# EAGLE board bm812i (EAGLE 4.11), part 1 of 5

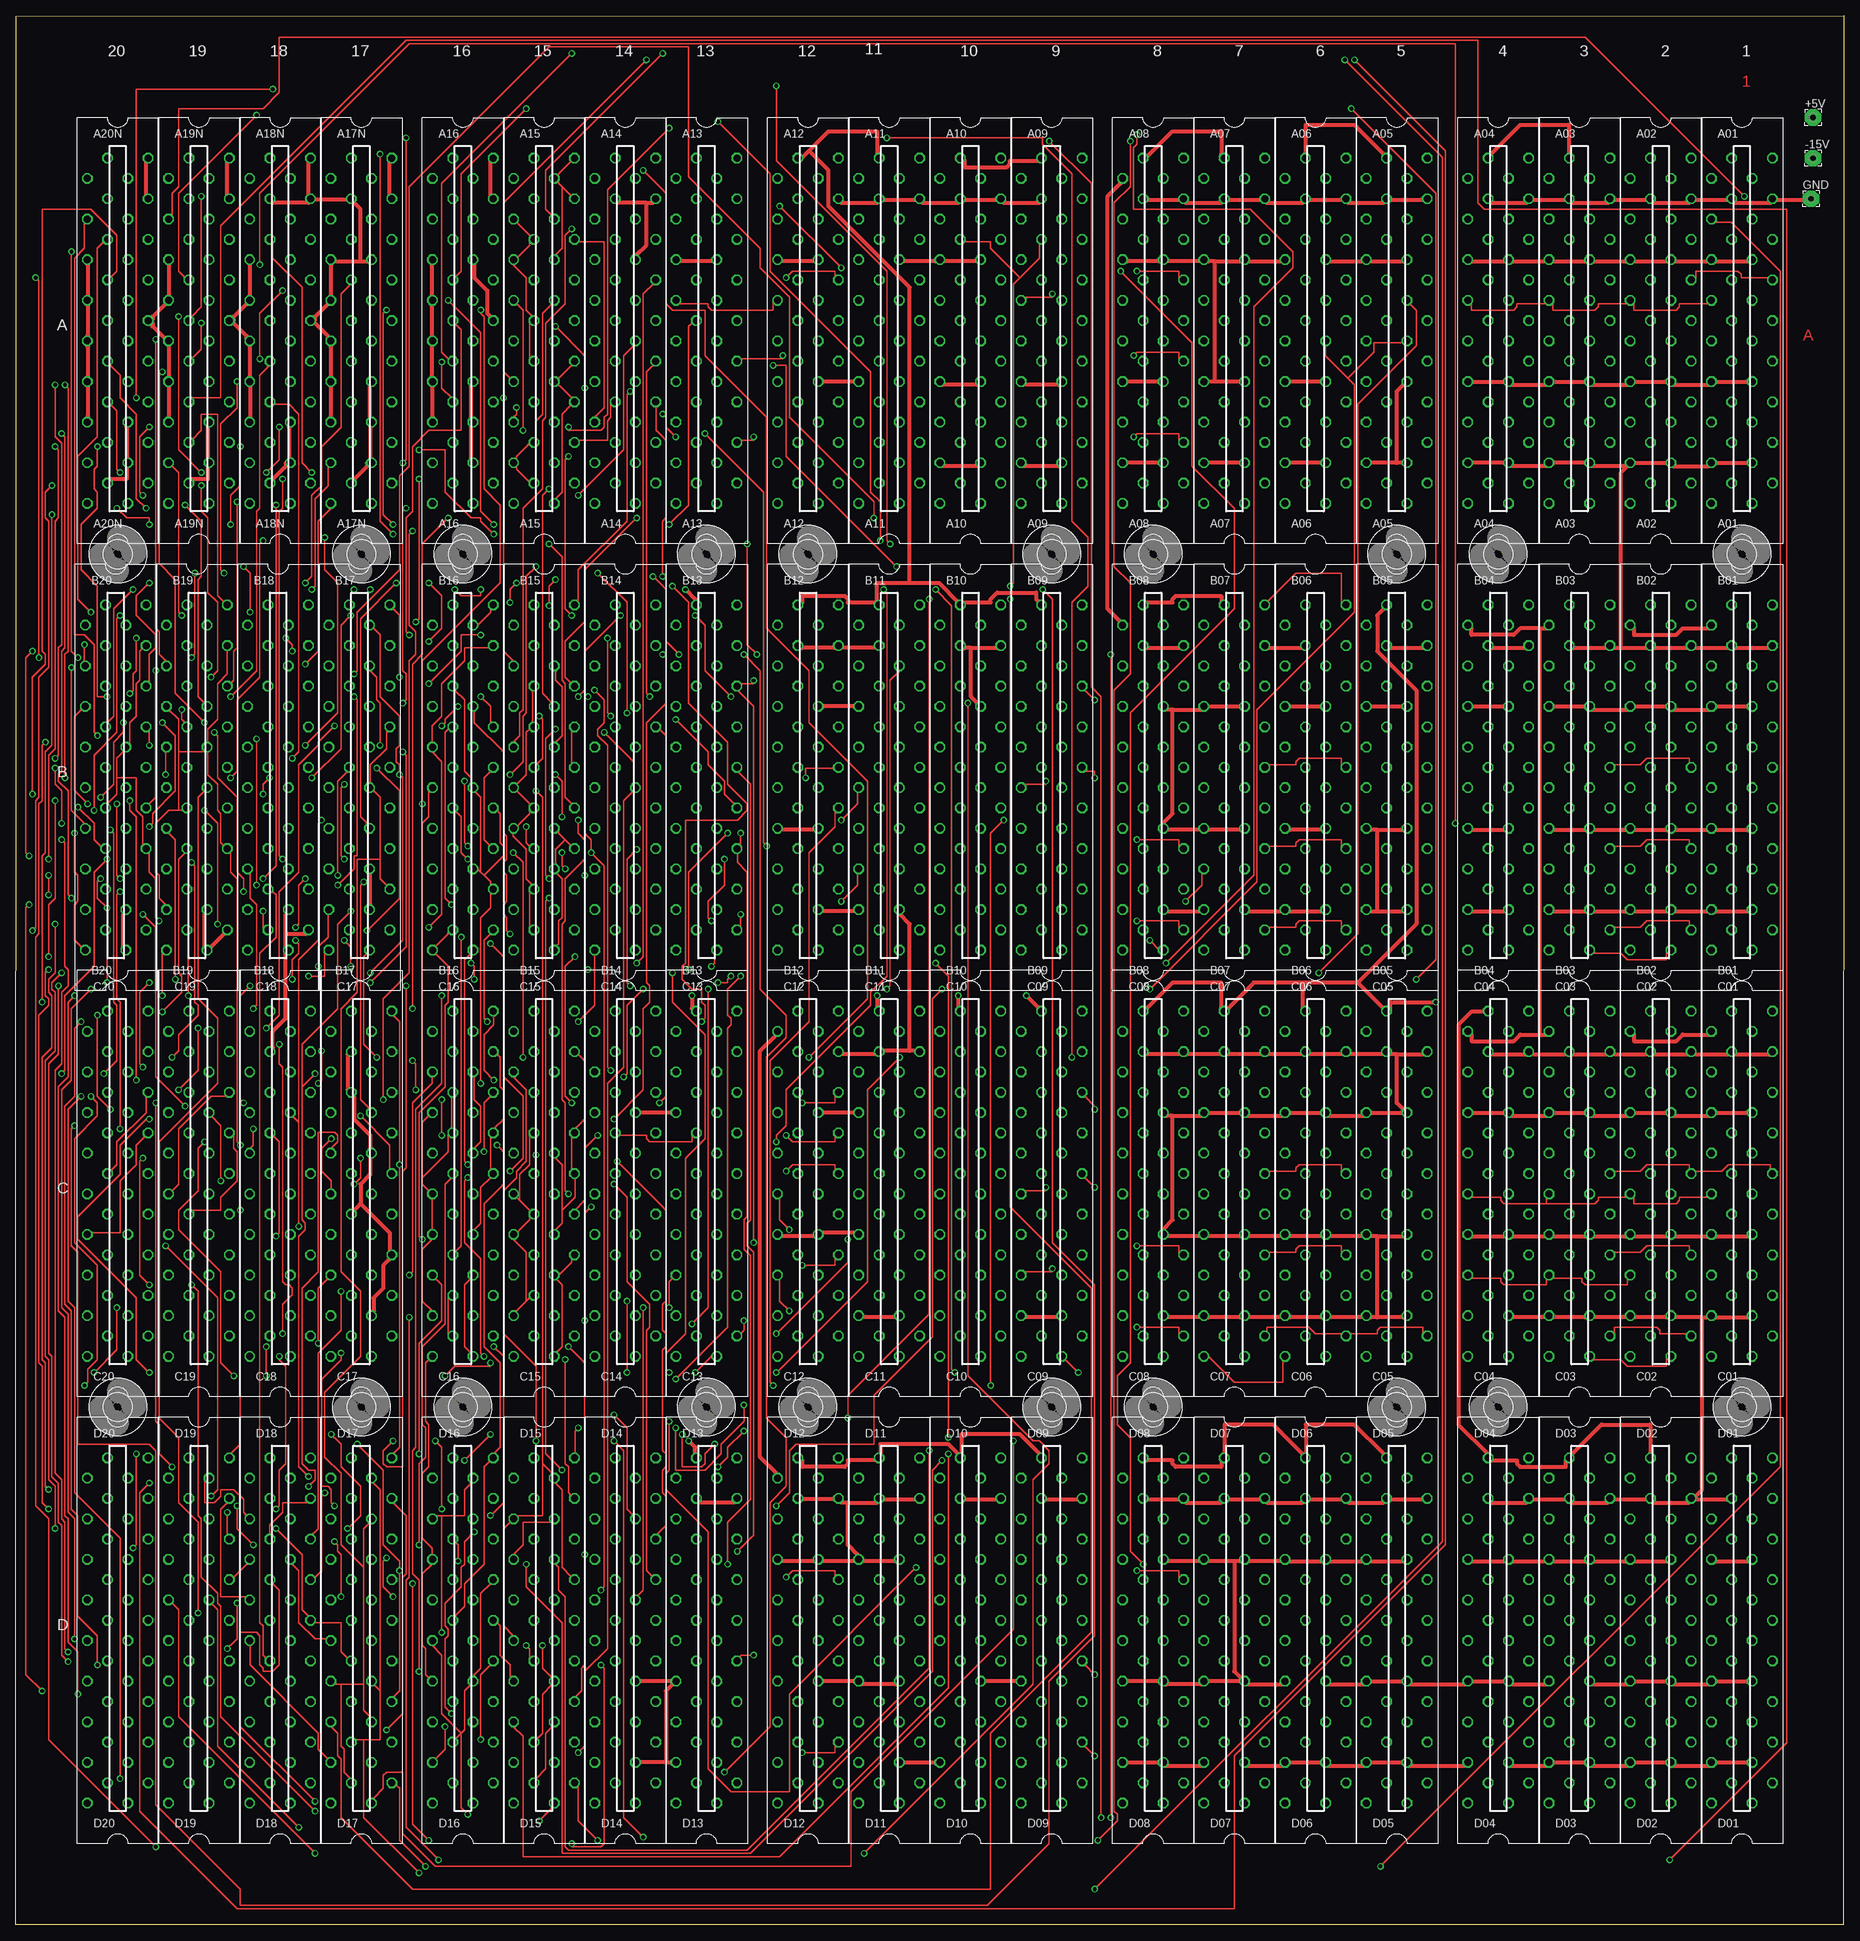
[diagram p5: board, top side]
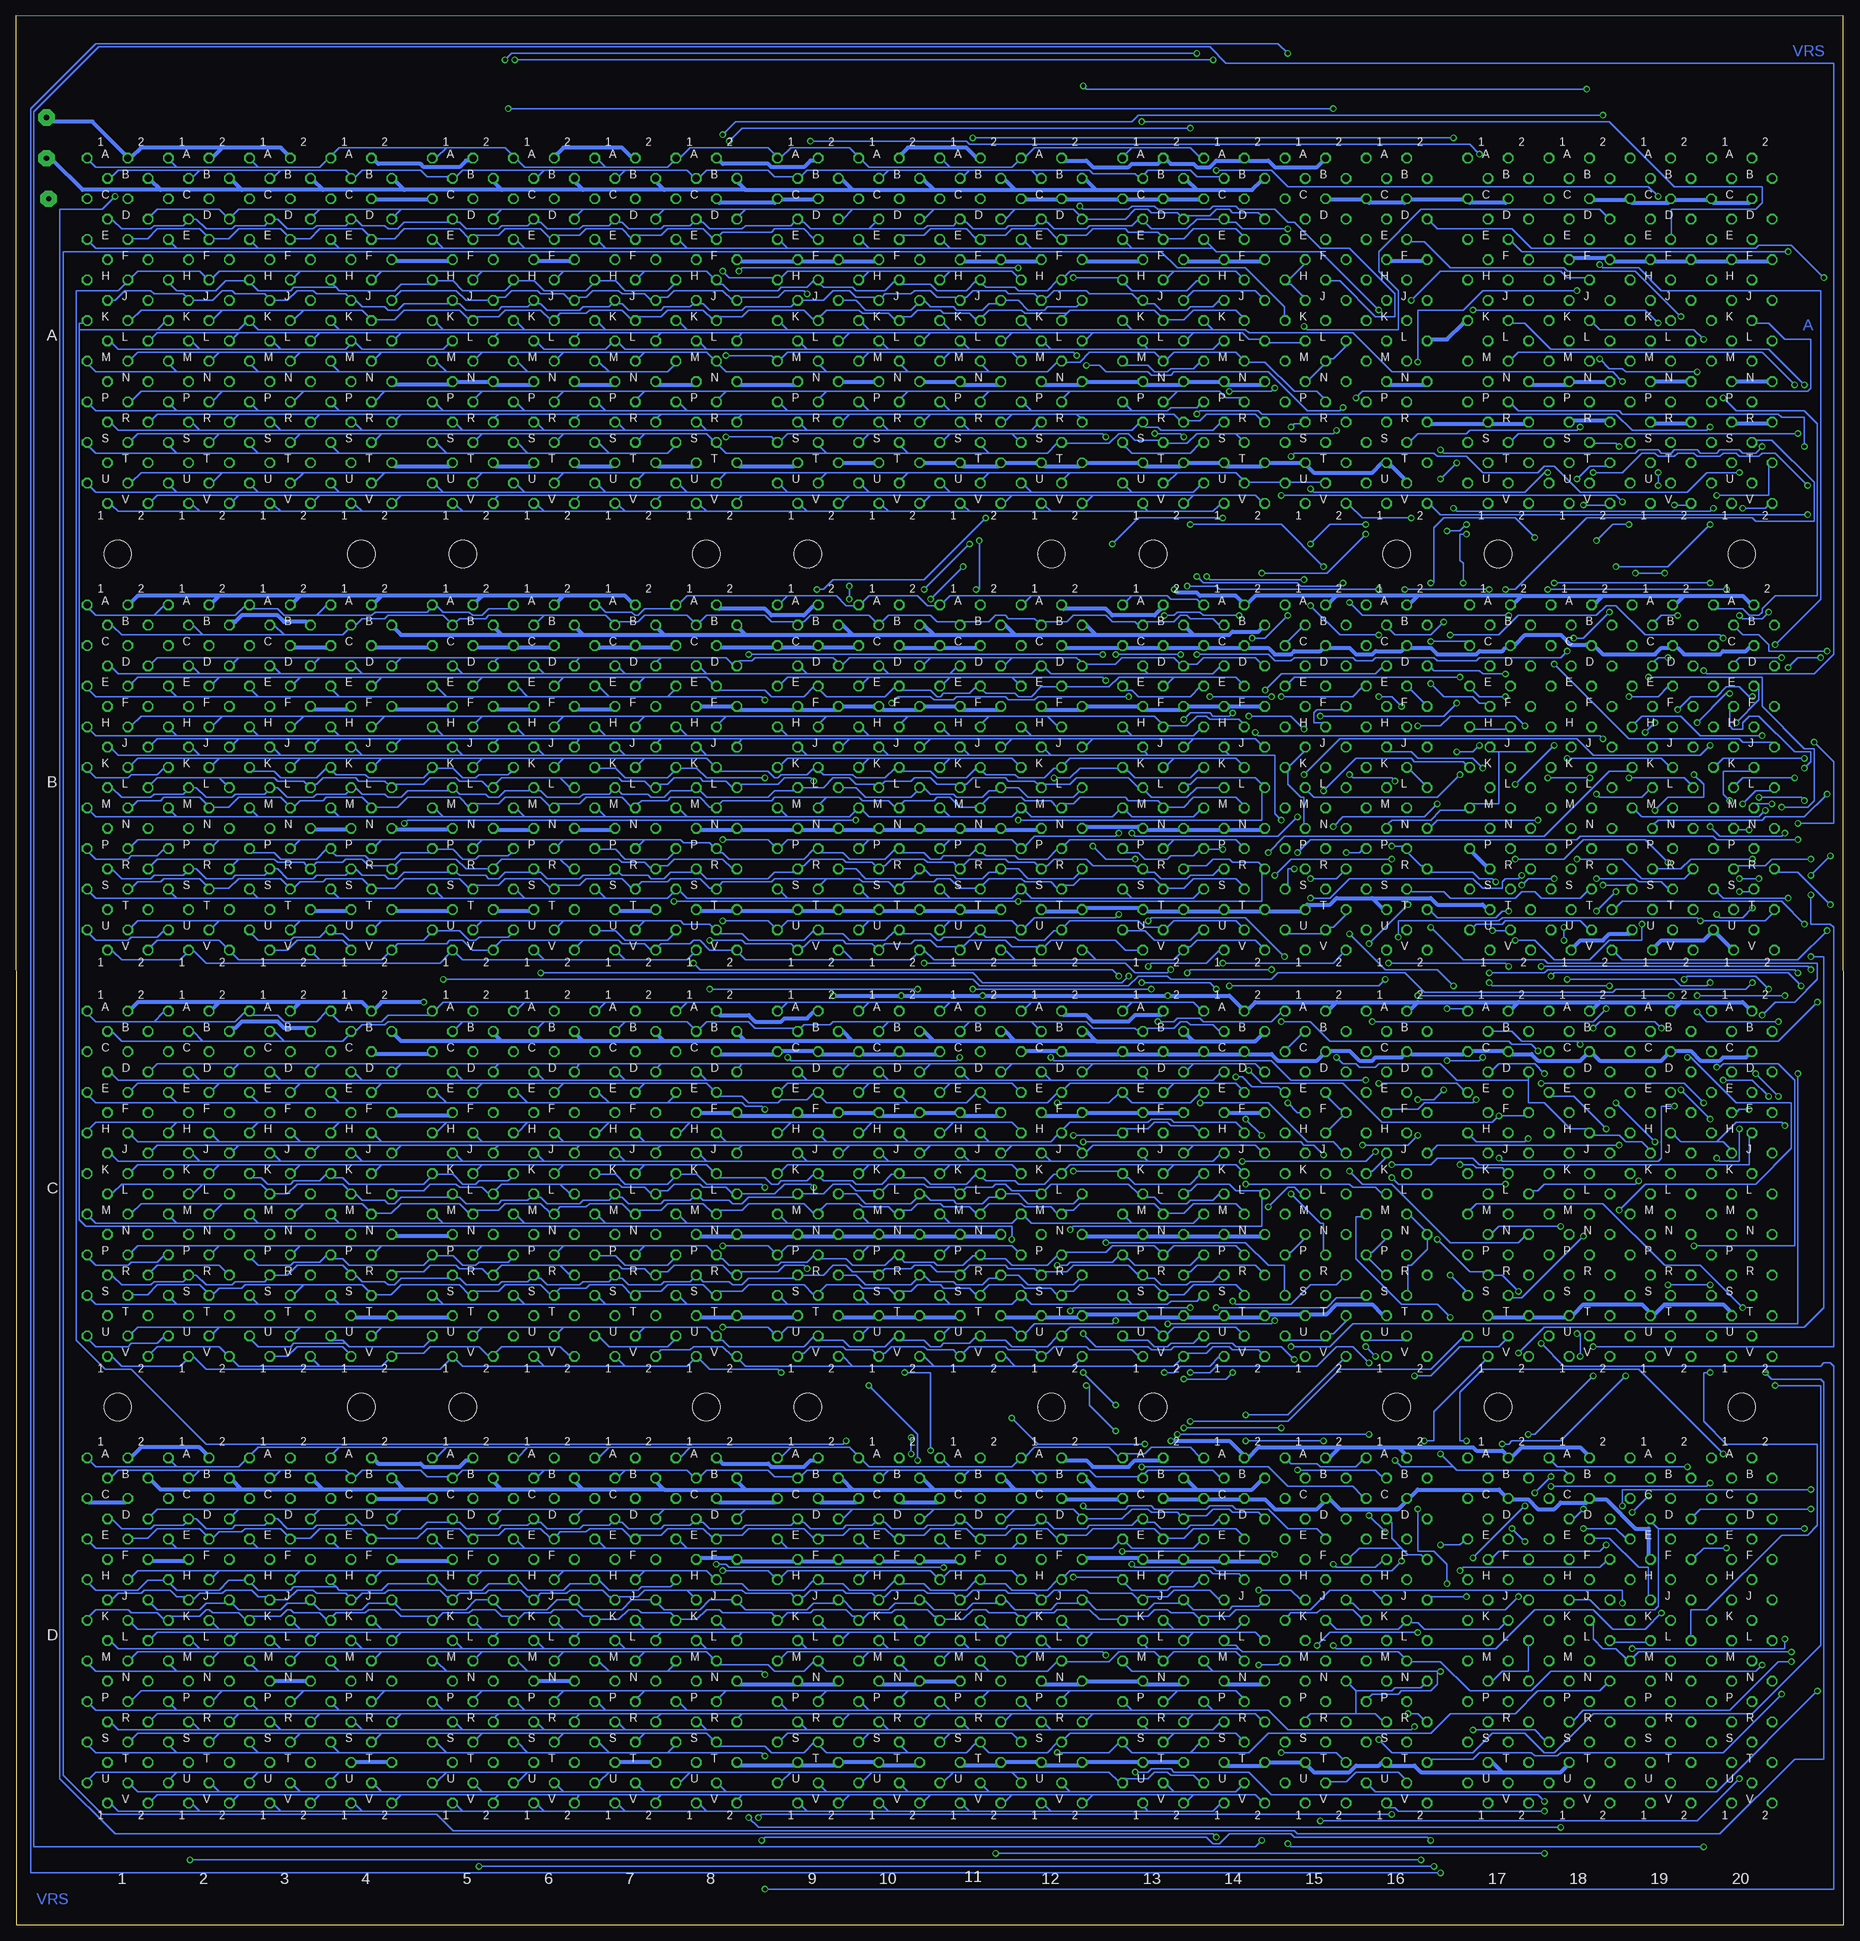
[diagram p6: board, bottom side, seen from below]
Size 285.81 x 298.44 mm. Coordinates in mm from the lower left corner, seen from the top.
Outline: 285.78,0 0,0 0.03,298.42 285.81,298.44 285.78,0
Copper layers (1*2*15*16): Top 0.035mm / dielectric 1.5mm / Route2 0.035mm / dielectric 0.15mm / Route15 0.035mm / dielectric 0.2mm / Bottom 0.035mm
Design rules "10mils": minimum track width 10mil, minimum drill 24mil, track to track 5mil, track to pad 10mil, pad to pad 10mil, via to via 5mil, smd to smd 10mil, copper to edge 40mil, drill to drill 10mil, minimum pad ring 10mil, minimum via ring 8mil, stop-mask expansion 0mil, vias tented up to drill 0mil, thermal gap 10mil
Net classes: 1 Power: width 0.635 mm

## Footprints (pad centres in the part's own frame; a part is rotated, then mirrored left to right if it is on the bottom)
2,54/0,8 = drill 0.813 pad 2.54 octagon: 1 0,0
H807 = drill 1.092 octagon: A1 4.763,28.575; A2 -1.587,28.575; B1 1.587,25.4; B2 -4.763,25.4; C1 4.763,22.225; C2 -1.587,22.225; D1 1.587,19.05; D2 -4.763,19.05; E1 4.763,15.875; E2 -1.587,15.875; F1 1.587,12.7; F2 -4.763,12.7; H1 4.763,9.525; H2 -1.587,9.525; J1 1.587,6.35; J2 -4.763,6.35; K1 4.763,3.175; K2 -1.587,3.175; L1 1.587,0; L2 -4.763,0; M1 4.763,-3.175; M2 -1.587,-3.175; N1 1.587,-6.35; N2 -4.763,-6.35; P1 4.763,-9.525; P2 -1.587,-9.525; R1 1.587,-12.7; R2 -4.763,-12.7; S1 4.763,-15.875; S2 -1.587,-15.875; T1 1.587,-19.05; T2 -4.763,-19.05; U1 4.763,-22.225; U2 -1.587,-22.225; V1 1.587,-25.4; V2 -4.763,-25.4
4,3 = hole 4.3: 0,0

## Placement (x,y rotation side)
+5V  [2,54/0,8]  281.02,282.56 0 top
-15V  [2,54/0,8]  281.02,276.21 0 top
A01  [H807]  269.91,247.64 0 top
A02  [H807]  257.21,247.64 0 top
A03  [H807]  244.51,247.64 0 top
A04  [H807]  231.81,247.64 0 top
A05  [H807]  215.94,247.64 0 top
A06  [H807]  203.24,247.64 0 top
A07  [H807]  190.54,247.64 0 top
A08  [H807]  177.84,247.64 0 top
A09  [H807]  161.96,247.64 0 top
A10  [H807]  149.26,247.64 0 top
A11  [H807]  136.56,247.64 0 top
A12  [H807]  123.86,247.64 0 top
A13  [H807]  107.99,247.64 0 top
A14  [H807]  95.29,247.64 0 top
A15  [H807]  82.59,247.64 0 top
A16  M903  [H807]  69.89,247.64 0 top
A17N  M903  [H807]  54.01,247.64 0 top
A18N  M903  [H807]  41.31,247.64 0 top
A19N  M903  [H807]  28.61,247.64 0 top
A20N  M903  [H807]  15.91,247.64 0 top
B01  [H807]  269.91,177.79 0 top
B02  [H807]  257.21,177.79 0 top
B03  [H807]  244.51,177.79 0 top
B04  [H807]  231.81,177.79 0 top
B05  [H807]  215.94,177.79 0 top
B06  [H807]  203.24,177.79 0 top
B07  [H807]  190.54,177.79 0 top
B08  [H807]  177.84,177.79 0 top
B09  [H807]  161.96,177.79 0 top
B10  [H807]  149.26,177.79 0 top
B11  [H807]  136.56,177.79 0 top
B12  [H807]  123.86,177.79 0 top
B13  [H807]  107.99,177.79 0 top
B14  [H807]  95.29,177.79 0 top
B15  [H807]  82.59,177.79 0 top
B16  [H807]  69.89,177.79 0 top
B17  [H807]  53.69,177.79 0 top
B18  [H807]  40.99,177.79 0 top
B19  [H807]  28.29,177.79 0 top
B20  [H807]  15.59,177.79 0 top
C01  [H807]  269.91,114.29 0 top
C02  [H807]  257.21,114.29 0 top
C03  [H807]  244.51,114.29 0 top
C04  [H807]  231.81,114.29 0 top
C05  [H807]  215.94,114.29 0 top
C06  [H807]  203.24,114.29 0 top
C07  [H807]  190.54,114.29 0 top
C08  [H807]  177.84,114.29 0 top
C09  [H807]  161.96,114.29 0 top
C10  [H807]  149.26,114.29 0 top
C11  [H807]  136.56,114.29 0 top
C12  [H807]  123.86,114.29 0 top
C13  [H807]  107.99,114.29 0 top
C14  [H807]  95.29,114.29 0 top
C15  [H807]  82.59,114.29 0 top
C16  [H807]  69.89,114.29 0 top
C17  M206X  [H807]  54.01,114.29 0 top
C18  M310  [H807]  41.31,114.29 0 top
C19  M310  [H807]  28.61,114.29 0 top
C20  M310  [H807]  15.91,114.29 0 top
D01  [H807]  269.91,44.44 0 top
D02  [H807]  257.21,44.44 0 top
D03  [H807]  244.51,44.44 0 top
D04  [H807]  231.81,44.44 0 top
D05  [H807]  215.94,44.44 0 top
D06  [H807]  203.24,44.44 0 top
D07  [H807]  190.54,44.44 0 top
D08  [H807]  177.84,44.44 0 top
D09  [H807]  161.96,44.44 0 top
D10  [H807]  149.26,44.44 0 top
D11  [H807]  136.56,44.44 0 top
D12  [H807]  123.86,44.44 0 top
D13  [H807]  107.99,44.44 0 top
D14  [H807]  95.29,44.44 0 top
D15  M206X  [H807]  82.59,44.44 0 top
D16  M206X  [H807]  69.89,44.44 0 top
D17  M206X  [H807]  54.01,44.44 0 top
D18  [H807]  41.31,44.44 0 top
D19  M921  [H807]  28.61,44.44 0 top
D20  H807  [H807]  15.91,44.44 0 top
GND  [2,54/0,8]  280.71,269.86 0 top
U$20  [4,3]  15.91,214.3 0 top
U$66  [4,3]  54.01,214.3 0 top
U$67  [4,3]  69.89,214.3 0 top
U$68  [4,3]  107.99,214.3 0 top
U$69  [4,3]  123.86,214.3 0 top
U$70  [4,3]  161.96,214.3 0 top
U$71  [4,3]  177.84,214.3 0 top
U$72  [4,3]  215.94,214.3 0 top
U$73  [4,3]  231.81,214.3 0 top
U$74  [4,3]  269.91,214.3 0 top
U$75  [4,3]  269.91,80.95 0 top
U$76  [4,3]  231.81,80.95 0 top
U$77  [4,3]  215.94,80.95 0 top
U$78  [4,3]  177.84,80.95 0 top
U$79  [4,3]  161.96,80.95 0 top
U$80  [4,3]  123.86,80.95 0 top
U$81  [4,3]  107.99,80.95 0 top
U$82  [4,3]  69.89,80.95 0 top
U$83  [4,3]  54.01,80.95 0 top
U$86  [4,3]  15.91,80.95 0 top

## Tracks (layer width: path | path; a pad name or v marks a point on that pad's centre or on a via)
-15V
  Top 0.635: B01.B2 264.7,202.68 260.64,202.68 259.62,201.66 253.02,201.66 253.02,202.68 B02.B2 | 238.29,202.68 235.24,202.68 234.22,201.66 227.62,201.66 227.62,202.68 B04.B2 | 238.29,202.68 239.3,202.68 B03.B2 | C01.B2 264.7,139.18 260.64,139.18 259.62,138.16 253.02,138.16 253.02,139.18 C02.B2 | 238.29,139.18 235.24,139.18 234.22,138.16 227.62,138.16 227.62,139.18 C04.B2 | 238.29,139.18 239.3,139.18 C03.B2 | D12.B2 118.91,70.6 116.37,73.14 116.37,136.64 118.91,139.18 C12.B2 | 238.29,139.18 238.29,202.68 | A08.B2 172.76,272.28 170.72,270.24 170.72,205.73 172.76,203.7 B08.B2
  Bottom 0.635: 101.13,271.26 92.49,271.26 90.97,272.78 A14.B2 | 101.13,271.26 102.65,272.78 A13.B2 | 116.88,271.26 118.4,272.78 A12.B2 | 116.88,271.26 101.13,271.26 | 129.58,271.26 131.1,272.78 A11.B2 | 129.58,271.26 116.88,271.26 | 142.28,271.26 143.8,272.78 A10.B2 | 142.28,271.26 129.58,271.26 | 154.98,271.26 156.5,272.78 A09.B2 | 154.98,271.26 142.28,271.26 | 171.74,271.26 172.76,272.28 A08.B2 | 171.74,271.26 154.98,271.26 | 184.44,271.26 185.46,272.28 A07.B2 | 171.74,271.26 184.44,271.26 | 197.14,271.26 198.16,272.28 A06.B2 | 184.44,271.26 197.14,271.26 | 209.84,271.26 210.86,272.28 A05.B2 | 197.14,271.26 209.84,271.26 | 225.08,271.26 226.6,272.78 A04.B2 | 209.84,271.26 225.08,271.26 | 237.78,271.26 239.3,272.78 A03.B2 | 225.08,271.26 237.78,271.26 | 250.48,271.26 252,272.78 A02.B2 | 237.78,271.26 250.48,271.26 | 263.18,271.26 264.7,272.78 A01.B2 | 250.48,271.26 263.18,271.26 | 263.18,271.26 275.37,271.26 279.94,275.83 -15V.1 | B03.B2 240.32,203.7 243.88,203.7 244.89,204.71 250.48,204.71 251.5,203.7 252,203.7 B02.B2 | 101.64,201.66 96.05,201.66 95.54,202.17 91.48,202.17 90.97,202.68 B14.B2 | 101.64,201.66 102.65,202.68 B13.B2 | 116.88,201.66 118.4,203.19 B12.B2 | 116.88,201.66 101.64,201.66 | 129.58,201.66 131.1,203.19 B11.B2 | 129.58,201.66 116.88,201.66 | 142.28,201.66 143.8,203.19 B10.B2 | 142.28,201.66 129.58,201.66 | 154.98,201.66 156.5,203.19 B09.B2 | 154.98,201.66 142.28,201.66 | 171.74,201.66 172.76,202.68 B08.B2 | 171.74,201.66 154.98,201.66 | 184.44,201.66 185.46,202.68 B07.B2 | 184.44,201.66 171.74,201.66 | 197.14,201.66 198.16,202.68 B06.B2 | 197.14,201.66 184.44,201.66 | 209.84,201.66 210.86,202.68 B05.B2
  Bottom 0.635: 209.84,201.66 197.14,201.66 | 209.84,201.66 225.59,201.66 226.6,202.68 B04.B2 | 101.13,68.06 92.49,68.06 90.97,69.58 D14.B2 | 101.13,68.06 102.65,69.58 D13.B2 | 116.88,68.06 118.4,69.58 D12.B2 | 116.88,68.06 101.13,68.06 | 129.58,68.06 131.1,69.58 D11.B2 | 129.58,68.06 116.88,68.06 | 142.28,68.06 143.8,69.58 D10.B2 | 142.28,68.06 129.58,68.06 | 154.98,68.06 156.5,69.58 D09.B2 | 154.98,68.06 142.28,68.06 | 171.74,68.06 172.76,69.08 D08.B2 | 171.74,68.06 154.98,68.06 | 184.44,68.06 185.46,69.08 D07.B2 | 184.44,68.06 171.74,68.06 | 197.14,68.06 198.16,69.08 D06.B2 | 184.44,68.06 197.14,68.06 | 209.84,68.06 210.86,69.08 D05.B2 | 197.14,68.06 209.84,68.06 | 225.08,68.06 226.6,69.58 D04.B2 | 209.84,68.06 225.08,68.06 | 237.78,68.06 239.3,69.58 D03.B2 | 225.08,68.06 237.78,68.06 | 250.48,68.06 252,69.58 D02.B2 | 237.78,68.06 250.48,68.06 | 250.48,68.06 263.18,68.06 264.7,69.58 D01.B2 | C03.B2 240.32,140.2 243.88,140.2 244.89,141.21 250.48,141.21 251.5,140.2 252,140.2 C02.B2 | 101.64,138.16 91.98,138.16 90.97,139.18 C14.B2 | 101.64,138.16 102.65,139.18 C13.B2 | 116.88,138.16 118.4,139.69 C12.B2 | 116.88,138.16 101.64,138.16 | 129.58,138.16 131.1,139.69 C11.B2 | 116.88,138.16 129.58,138.16 | 142.28,138.16 143.8,139.69 C10.B2 | 129.58,138.16 142.28,138.16 | 154.98,138.16 156.5,139.69 C09.B2 | 142.28,138.16 154.98,138.16 | 171.74,138.16 172.76,139.18 C08.B2 | 154.98,138.16 171.74,138.16 | 184.44,138.16 185.46,139.18 C07.B2 | 171.74,138.16 184.44,138.16 | 197.14,138.16 198.16,139.18 C06.B2 | 184.44,138.16 197.14,138.16 | 209.84,138.16 210.86,139.18 C05.B2 | 197.14,138.16 209.84,138.16 | 209.84,138.16 225.59,138.16 226.6,139.18 C04.B2
A15U1
  Top 0.254: 85.38,271.77 84.87,272.28 84.87,272.78 A15.B1 84.87,273.29 84.87,273.8 86.9,275.83 A15.A1 | 85.38,271.77 86.9,270.24 A15.C1 | 85.38,271.77 85.38,262.12 84.36,261.1 A15.F1 | A15.U2 80.3,225.54 78.27,227.57 78.27,228.08 A15.T2 78.27,229.1 78.27,229.6 80.3,231.64 A15.S2 81.32,232.14 81.32,235.19 82.33,236.21 82.33,251.96 83.86,253.48 A15.J1
  Bottom 0.254: A15.J1 84.36,254.5 86.4,256.53 86.9,256.53 A15.H1 86.9,257.54 86.4,257.54 84.36,259.58 A15.F1 | 104.18,227.06 105.7,225.54 A13.U2 | 104.18,227.06 95.03,227.06 94.02,226.05 A14.U2 93,225.54 87.92,225.54 A15.U1 86.9,225.54 81.32,225.54 A15.U2 | 120.94,227.06 121.96,226.05 A12.U2 | 104.18,227.06 120.94,227.06 | 133.64,227.06 134.66,226.05 A11.U2 | 120.94,227.06 133.64,227.06 | 146.34,227.06 147.36,226.05 A10.U2 | 133.64,227.06 146.34,227.06 | 159.04,227.06 160.06,226.05 A09.U2 | 146.34,227.06 159.04,227.06 | 174.79,227.06 175.8,226.05 A08.U2 | 159.04,227.06 174.79,227.06 | 187.49,227.06 188.5,226.05 A07.U2 | 174.79,227.06 187.49,227.06 | 200.19,227.06 201.2,226.05 A06.U2 | 187.49,227.06 200.19,227.06 | 212.89,227.06 213.9,226.05 A05.U2 | 200.19,227.06 212.89,227.06 | 228.13,227.06 229.65,225.54 A04.U2 | 212.89,227.06 228.13,227.06 | 240.83,227.06 242.35,225.54 A03.U2 | 228.13,227.06 240.83,227.06 | 253.53,227.06 255.05,225.54 A02.U2 | 240.83,227.06 253.53,227.06 | 253.53,227.06 266.23,227.06 267.75,225.54 A01.U2
A15V1
  Top 0.254: A15.V1 84.36,223 85.38,224.02 85.38,236.21 86.9,237.73 A15.P1 86.9,238.75 84.87,240.78 84.87,241.29 | A15.D2 78.27,266.18 80.3,264.15 80.3,263.64 A15.E2 80.3,263.13 80.3,262.62 78.27,260.59 A15.F2 77.76,259.58 79.79,257.54 79.79,252.46 80.81,251.45 A15.K2 80.3,250.43 80.3,244.84 A15.M2 | 84.87,241.29 84.87,241.8 86.9,243.83 A15.M1 | 84.87,241.29 A15.N1
  Bottom 0.254: A15.N1 83.86,241.8 83.35,241.8 81.32,243.83 A15.M2 80.3,244.84 79.79,244.84 77.76,246.88 A15.L2
B17S1
  Top 0.254: B17.H1 57.95,186.93 57.95,183.88 55.41,181.34 55.41,178.3 B17.L1 55.92,177.28 56.93,176.26 56.93,166.61 | 56.93,166.61 56.93,163.56 57.95,162.55 B17.S1 | 50.84,37.58 54.39,37.58 | 50.84,37.58 49.82,37.58 D17.N2 | 54.39,37.58 54.39,33.52 55.41,32.5 D17.R1 | 50.84,37.58 50.84,27.93 51.34,27.42 51.34,23.86 52.36,22.85 D17.U2 | 54.39,37.58 54.39,55.87 | 54.39,55.87 54.39,61.96 55.41,62.98 D17.D1 | 56.93,166.61 53.38,166.61 53.38,145.78 50.84,143.24 50.84,102.1 53.88,99.05 53.88,88.89 48.3,83.3 48.3,73.14 50.84,70.6 50.84,59.42 54.39,55.87
  Bottom 0.254: B17.H2 52.87,186.93 57.95,186.93 B17.H1
B17V1  (via drill 0.61)
  Top 0.254: B16.B1 72.17,203.19 74.2,205.22 74.2,205.73 B16.A1 | v56.42,135.62 54.39,137.66 54.39,151.37 54.9,151.88 B17.V1 | v62.01,135.12 62.52,134.61 v62.52,130.54 | v66.58,123.43 v66.58,129.02 | v75.22,121.91 76.24,120.89 76.24,115.81 73.19,112.76 73.19,90.41 75.73,87.87 75.73,74.66 74.71,73.65 D16.A1 74.2,72.63 73.19,71.62 73.19,56.38 70.14,53.33 70.14,49.77 68.62,48.25 D16.K2 | v62.52,203.7 63.03,204.2 v63.03,226.05 | v60.49,228.59 61,229.1 v61,279.39 | v136.18,279.39 160.56,279.39 160.56,278.37 165.14,273.8 165.14,219.44 167.68,216.9 167.68,209.28 165.14,206.74 v165.14,135.62 | v138.21,135.62 133.13,130.54 133.13,100.57 v118.91,86.35 | v113.83,81.27 113.83,78.73 110.27,75.17 110.27,73.65 107.73,71.11 103.16,71.11 v103.16,77.71 | v87.92,77.71 87.41,77.2 87.41,73.65 D15.A1
  Bottom 0.254: D17.K2 52.87,47.23 53.88,46.22 65.57,46.22 66.58,47.23 67.6,47.23 D16.K2 68.62,47.23 69.63,46.22 79.28,46.22 80.3,47.23 D15.K2 | v56.42,135.62 56.93,135.12 v62.01,135.12 | v62.52,130.54 64.04,129.02 v66.58,129.02 | v66.58,123.43 68.11,121.91 v75.22,121.91 | D15.A1 86.9,72.63 86.4,72.12 82.33,72.12 81.82,71.62 76.24,71.62 75.22,72.63 D16.A1 | v62.52,203.7 64.55,201.66 70.14,201.66 71.16,202.68 B16.B1 | v60.49,228.59 v63.03,226.05 | v136.18,279.39 v61,279.39 | v165.14,135.62 164.63,135.12 138.72,135.12 v138.21,135.62 | v118.91,86.35 v113.83,81.27 | v103.16,77.71 v87.92,77.71
C16U1
  Top 0.254: C16.S2 67.6,98.03 67.6,92.44 C16.U2 | C16.E2 68.11,129.53 68.11,124.45 C16.H2 67.6,123.43 67.6,120.89 63.54,116.83 | C16.T2 65.06,96 63.54,97.52 63.54,105.65 65.06,107.18 C16.N2 65.06,108.7 65.06,113.78 C16.L2 64.55,114.8 63.54,115.81 63.54,116.83 | 63.54,116.83 63.54,125.46 64.55,126.48 C16.F2
  Bottom 0.254: C16.U2 68.62,91.43 74.2,91.43 C16.U1 | C16.M2 67.6,110.73 65.57,108.7 65.06,108.7 C16.N2 65.06,107.18 65.06,105.65 67.6,103.11 68.11,103.11 68.11,99.05 C16.S2
D01BINIT  (via drill 0.61)
  Top 0.254: v63.03,73.65 63.03,90.92 66.58,94.48 66.58,100.06 65.57,101.08 C16.R2 | v78.27,237.22 78.27,236.21 77.76,235.7 A15.R2 | v118.4,243.83 120.43,243.83 120.43,229.6 v137.7,212.33 | v142.78,207.25 142.78,95.49 130.08,82.79 v130.08,79.24 | v109.26,75.17 107.73,73.65 107.73,72.12 107.22,71.62 104.18,71.62 v104.18,76.7 | v74.2,76.7 v70.14,72.63
  Bottom 0.254: 61,71.62 v63.03,73.65 | 61,71.62 60.49,71.11 43.72,71.11 43.22,70.6 D18.B1 | v78.27,237.22 78.78,236.72 83.86,236.72 89.95,242.81 104.68,242.81 105.19,242.3 108.24,242.3 108.75,242.81 115.35,242.81 116.37,243.83 v118.4,243.83 | v137.7,212.33 v142.78,207.25 | v130.08,79.24 126.02,75.17 v109.26,75.17 | v104.18,76.7 v74.2,76.7 | v70.14,72.63 69.12,71.62 61,71.62
D01BTP2L  (via drill 0.61)
  Top 0.254: B16.U2 67.6,155.44 67.6,154.93 65.57,152.9 B16.V2 65.57,151.88 67.6,149.85 67.6,144.26 67.09,143.75 67.09,131.05 63.03,126.99 63.03,107.68 v63.54,107.18 | v50.84,99.05 50.84,92.95 47.28,89.4 47.28,61.96 46.26,60.95 D18.E1
  Bottom 0.254: v50.84,99.05 53.38,101.59 C17.R1 55.92,102.1 58.46,102.1 v63.54,107.18
D01DEL1H  (via drill 0.61)
  Top 0.254: v14.77,127.5 12.74,129.53 v12.74,142.23 | v64.55,155.94 66.58,157.98 66.58,181.85 65.06,183.38 B16.J2 65.06,184.9 65.06,187.44 66.58,188.96 66.58,194.04 70.14,197.6 70.14,199.63 74.2,199.63 B16.C1
  Bottom 0.254: v14.77,127.5 16.29,127.5 16.8,126.99 C20.F1 | v12.74,142.23 10.7,144.26 7.66,144.26 4.1,147.82 4.1,150.36 46.26,150.36 46.77,150.86 59.47,150.86 v64.55,155.94
D01DEL1L  (via drill 0.61)
  Top 0.254: v53.88,126.48 58.46,121.91 58.46,117.84 C17.K1 | v90.46,193.03 91.98,191.5 91.98,187.95 90.97,186.93 90.97,185.92 92.49,184.39 92.49,134.1 v93,133.59
  Bottom 0.254: C17.F2 49.82,126.48 v53.88,126.48 54.9,125.46 72.17,125.46 78.27,131.56 90.97,131.56 v93,133.59 | v90.46,193.03 87.92,195.57 73.19,195.57 72.17,196.58 B16.D1
D01DEL2  (via drill 0.61)
  Top 0.254: v52.87,195.57 53.38,196.08 53.38,205.22 59.98,211.82 59.98,226.56 61.5,228.08 61.5,271.77 83.35,293.61 105.19,293.61 105.19,273.29 116.37,262.12 116.37,259.07 120.94,254.5 120.94,235.7 134.15,222.49 v134.15,219.95 | v160.56,208.78 162.09,207.25 162.09,106.67 168.69,100.06 168.69,45.2 161.58,38.09 161.58,12.69 151.93,3.04 35.09,3.04 35.09,5.58 21.88,18.78 21.88,74.16 20.86,75.17 9.69,75.17 9.69,105.14 8.67,106.16 8.67,124.45 v9.18,124.96
  Bottom 0.254: 19.85,122.42 25.44,122.42 26.45,123.43 C19.H2 | 19.85,122.42 18.83,122.42 17.82,121.4 C20.J1 | v52.87,195.57 56.42,195.57 56.93,196.08 64.04,196.08 64.55,196.58 B16.D2 | v134.15,219.95 143.8,210.3 158.02,210.3 159.55,208.78 v160.56,208.78 | v9.18,124.96 9.69,125.46 16.8,125.46 19.85,122.42
D01DEL3  (via drill 0.61)
  Top 0.254: v32.04,116.32 32.04,124.96 30.52,126.48 C19.F1 | v49.31,122.92 47.79,121.4 47.79,117.84 49.31,116.32 49.31,114.8 C17.L2
  Bottom 0.254: v32.04,116.32 32.55,115.81 46.77,115.81 47.79,114.8 48.8,114.8 C17.L2 | v49.31,122.92 49.82,122.42 57.44,122.42 58.46,123.43 C17.H1
D01DEL4  (via drill 0.61)
  Top 0.254: B16.P1 74.2,168.64 73.19,169.66 73.19,179.31 74.2,180.33 B16.K1 | v40.68,107.68 41.18,108.19 41.18,122.42 40.17,123.43 C18.H2 | v77.76,167.63 79.28,166.1 v79.28,135.62
  Bottom 0.254: C19.J1 30.52,121.4 31.53,122.42 34.07,122.42 35.09,123.43 39.15,123.43 C18.H2 40.17,124.45 42.71,124.45 46.77,128.51 49.31,128.51 49.31,132.07 | v40.68,107.68 50.33,98.03 51.85,98.03 C17.S2 | 49.31,132.07 49.31,132.58 C17.D2 | v77.76,167.63 75.73,167.63 75.22,168.14 B16.P1 | v79.28,135.62 78.27,134.61 76.24,134.61 75.73,134.1 73.19,134.1 72.68,134.61 63.03,134.61 60.49,132.07 49.31,132.07
D01DEL5  (via drill 0.61)
  Top 0.254: v44.23,109.21 44.23,125.46 | 44.23,125.46 43.22,126.48 C18.F1 | v47.79,172.71 47.28,172.2 47.28,153.91 44.23,150.86 44.23,125.46
  Bottom 0.254: v44.23,109.21 53.88,109.21 54.9,108.19 C17.N1 | v47.79,172.71 63.54,172.71 64.55,171.69 B16.N2
D01DONEH  (via drill 0.61)
  Top 0.254: v168.69,26.4 167.17,27.93 D09.S1 | v122.97,26.91 128.05,26.91 128.05,28.44 D12.S1
  Bottom 0.254: 102.14,26.91 100.62,28.44 D14.S1 | 102.14,26.91 111.29,26.91 112.3,27.93 D13.S1 113.32,28.44 114.84,26.91 v122.97,26.91 | 102.14,26.91 93,26.91 89.95,29.96 64.55,29.96 61.5,33.01 51.34,33.01 47.79,36.56 38.14,36.56 37.12,37.58 D18.N2 | 139.74,29.96 130.08,29.96 129.07,28.94 D12.S1 | 139.74,29.96 140.75,28.94 D11.S1 | 152.44,29.96 153.45,28.94 D10.S1 | 152.44,29.96 139.74,29.96 | 152.44,29.96 165.14,29.96 166.15,28.94 D09.S1 | 183.93,26.91 182.92,27.93 D08.S1 | 193.08,26.91 183.93,26.91 | 193.08,26.91 194.6,28.44 D07.S1 | 205.78,26.91 207.3,28.44 D06.S1 | 205.78,26.91 193.08,26.91 | 218.48,26.91 220,28.44 D05.S1 | 218.48,26.91 205.78,26.91 | 235.24,26.91 236.26,27.93 D04.S1 | 235.24,26.91 218.48,26.91 | 247.94,26.91 248.96,27.93 D03.S1 | 235.24,26.91 247.94,26.91 | 260.64,26.91 261.66,27.93 D02.S1 | 247.94,26.91 260.64,26.91 | 260.64,26.91 273.34,26.91 274.36,27.93 D01.S1 | v168.69,26.4 169.2,26.91 183.93,26.91
D01DONEL
  Top 0.254: D18.M2 39.15,41.64 38.64,42.15 38.64,46.72 38.14,47.23 38.14,151.88 40.68,154.42 40.68,161.02 40.17,161.53 B18.S2
  Bottom 0.254: B18.S2 40.17,161.53 41.18,160.52 47.28,160.52 48.3,161.53 50.33,161.53 51.34,160.52 61.5,160.52 62.52,161.53 67.6,161.53 B16.S2
D01INHIBIT
  Top 0.254: A15.S1 87.92,232.14 92.49,232.14 92.49,235.19 93,235.7 93,237.73 A14.P2
  Bottom 0.254: 104.18,239.76 105.7,238.24 A13.P2 | 104.18,239.76 97.57,239.76 96.56,238.75 94.02,238.75 A14.P2 | 120.94,239.76 121.96,238.75 A12.P2 | 104.18,239.76 120.94,239.76 | 133.64,239.76 134.66,238.75 A11.P2 | 120.94,239.76 133.64,239.76 | 146.34,239.76 147.36,238.75 A10.P2 | 133.64,239.76 146.34,239.76 | 159.04,239.76 160.06,238.75 A09.P2 | 146.34,239.76 159.04,239.76 | 174.79,239.76 175.8,238.75 A08.P2 | 159.04,239.76 174.79,239.76 | 187.49,239.76 188.5,238.75 A07.P2 | 174.79,239.76 187.49,239.76 | 200.19,239.76 201.2,238.75 A06.P2 | 187.49,239.76 200.19,239.76 | 212.89,239.76 213.9,238.75 A05.P2 | 200.19,239.76 212.89,239.76 | 228.13,239.76 229.65,238.24 A04.P2 | 212.89,239.76 228.13,239.76 | 240.83,239.76 242.35,238.24 A03.P2 | 228.13,239.76 240.83,239.76 | 253.53,239.76 255.05,238.24 A02.P2 | 240.83,239.76 253.53,239.76 | 253.53,239.76 266.23,239.76 267.75,238.24 A01.P2
D01INITL  (via drill 0.61)
  Top 0.254: C17.A1 58.96,142.23 59.98,141.21 v59.98,118.86 59.98,74.66 58.96,73.65 D17.A1 | v67.6,219.95 63.54,215.89 63.54,198.62 62.01,197.09 v62.01,143.24
  Bottom 0.254: v59.98,118.86 57.95,118.86 57.44,118.35 53.38,118.35 52.87,117.84 C17.K2 | v67.6,219.95 75.22,219.95 77.25,221.98 A15.V2 | v62.01,143.24 59.47,143.24 C17.A1
D01LOADMDL
  Bottom 0.254: 53.88,183.38 54.9,183.38 B17.J1 | 53.88,183.38 49.31,183.38 B17.J2 | B16.N1 71.16,172.2 70.65,172.71 64.55,172.71 63.03,174.23 58.96,174.23 B17.M1 57.95,175.25 53.88,175.25 53.88,183.38
D01MEMDONEL  (via drill 0.61)
  Top 0.254: v2.58,155.44 3.08,155.94 3.08,175.76 3.59,176.26 3.59,195.06 5.12,196.58 5.12,219.44 4.61,219.95 4.61,224.02 v5.62,225.03 | v39.15,227.06 41.18,229.1 v41.18,234.18
  Bottom 0.254: v2.58,155.44 7.15,150.86 34.58,150.86 35.6,151.88 B18.V2 | v5.62,225.03 10.7,230.11 12.74,230.11 13.24,229.6 16.29,229.6 16.8,230.11 18.83,230.11 19.34,229.6 22.9,229.6 23.4,230.11 25.94,230.11 26.45,229.6 28.99,229.6 29.5,230.11 31.53,230.11 34.58,227.06 v39.15,227.06 | v41.18,234.18 41.69,233.67 58.46,233.67 58.96,233.16 66.58,233.16 67.6,232.14 A16.S2
D01MEMSTARTL  (via drill 0.61)
  Top 0.254: v48.3,67.55 47.79,67.04 47.79,55.36 46.77,54.34 D18.H1 | v45.76,70.09 44.23,71.62 44.23,107.68 45.25,108.7 45.25,109.72 44.74,110.22 44.74,131.05 | 44.74,131.05 v46.77,133.08 | v52.36,158.48 50.33,156.45 50.33,143.24 44.74,137.66 44.74,131.05
  Bottom 0.254: v48.3,67.55 v45.76,70.09 | v46.77,133.08 48.3,134.61 53.88,134.61 54.9,133.59 C17.D1 | v52.36,158.48 53.38,158.48 54.39,157.47 63.54,157.47 64.55,158.48 B16.T2
D01POWEROK  (via drill 0.61)
  Top 0.254: v24.42,71.62 22.39,73.65 22.39,78.22 21.88,78.73 v21.88,128.51 | v47.28,131.56 47.79,132.07 v47.79,136.64 | v87.92,141.21 90.46,143.75 90.46,151.88 B14.V2
  Bottom 0.254: v24.42,71.62 44.74,71.62 45.76,72.63 D18.A1 | v21.88,128.51 24.93,131.56 v47.28,131.56 | v47.79,136.64 48.8,137.66 51.85,137.66 52.36,138.16 80.3,138.16 83.35,141.21 v87.92,141.21 | 238.29,150.86 228.64,150.86 227.62,151.88 B04.V2 226.6,152.9 226.1,153.4 218.48,153.4 217.97,153.91 215.94,153.91 214.41,152.39 B05.V2 210.86,152.9 209.84,153.91 197.14,153.91 | 238.29,150.86 239.3,151.88 B03.V2 | 238.29,150.86 250.99,150.86 252,151.88 B02.V2 253.02,152.9 254.04,153.91 263.69,153.91 264.7,152.9 B01.V2 | 197.14,153.91 191.55,153.91 191.04,153.4 187.49,153.4 186.47,152.39 B07.V2 185.46,152.9 184.95,153.4 180.38,153.4 179.87,153.91 178.85,153.91 177.33,152.39 B08.V2 172.76,151.88 171.74,150.86 154.98,150.86 | 197.14,153.91 198.16,152.9 B06.V2 | 116.88,150.86 104.68,150.86 103.67,151.88 B13.V2 102.65,152.9 102.14,152.9 101.13,153.91 91.98,153.91 90.97,152.9 B14.V2 | 116.88,150.86 118.4,152.39 B12.V2 | 129.58,150.86 131.1,152.39 B11.V2 | 116.88,150.86 129.58,150.86 | 129.58,150.86 142.28,150.86 143.8,152.39 B10.V2 144.82,151.88 145.83,150.86 154.98,150.86 | 154.98,150.86 156.5,152.39 B09.V2
D01READH  (via drill 0.61)
  Top 0.254: v72.68,131.56 72.68,157.47 74.2,158.99 74.2,161.53 B16.S1 74.2,162.55 74.2,163.06 73.19,164.07 | 72.68,164.58 73.19,164.07 | 72.68,164.58 72.17,165.09 B16.R1 | 72.68,164.58 72.68,176.26 71.66,177.28 B16.L1 71.16,178.3 71.16,179.31 70.14,180.33 70.14,191.5 68.62,193.03 B16.E2 | 73.19,164.07 76.24,167.12 76.24,168.64 75.73,169.15 75.73,173.72 75.22,174.23 B16.M1
  Bottom 0.254: B16.F2 65.57,191 67.6,193.03 68.11,193.03 B16.E2 | v72.68,131.56 60.49,131.56 59.47,130.54 C17.E1
D01READL  (via drill 0.61)
  Top 0.254: v54.39,163.06 53.88,162.55 53.88,129.02 55.41,127.5 C17.F1 | v70.65,168.64 70.14,169.15 v70.14,178.8 | v77.25,179.82 79.28,181.85 79.28,188.96 79.79,189.47 79.79,210.81 v81.32,212.33 | v102.14,218.94 105.19,221.98 105.19,249.92 105.7,250.43 A13.K2
  Bottom 0.254: 240.83,252.46 231.68,252.46 230.67,251.45 A04.K2 229.65,250.94 226.6,250.94 225.08,252.46 216.44,252.46 214.92,250.94 A05.K2 213.9,251.45 210.35,251.45 209.33,252.46 203.74,252.46 202.22,250.94 A06.K2 201.2,251.45 200.7,251.96 196.63,251.96 196.12,252.46 191.04,252.46 189.52,250.94 A07.K2 188.5,251.45 184.95,251.45 183.93,252.46 178.34,252.46 176.82,250.94 A08.K2 175.8,251.45 172.25,251.45 171.23,252.46 162.6,252.46 161.07,250.94 A09.K2 160.06,251.45 159.04,252.46 153.96,252.46 153.45,251.96 149.39,251.96 148.37,250.94 A10.K2 147.36,251.45 145.83,251.45 144.82,252.46 141.26,252.46 140.75,251.96 136.69,251.96 135.67,250.94 A11.K2 134.66,251.45 133.64,252.46 128.56,252.46 128.05,251.96 121.45,251.96 | 240.83,252.46 242.35,250.94 A03.K2 | 253.53,252.46 255.05,250.94 A02.K2 | 240.83,252.46 253.53,252.46 | 253.53,252.46 266.23,252.46 267.75,250.94 A01.K2 | v54.39,163.06 54.9,163.56 56.93,163.56 57.95,164.58 64.55,164.58 B16.R2 65.57,165.6 66.08,165.6 68.11,167.63 B16.P2 68.62,168.64 v70.65,168.64 | A14.K2 94.02,251.45 95.03,252.46 101.64,252.46 103.16,250.94 105.7,250.94 A13.K2 106.72,251.45 107.73,252.46 120.94,252.46 121.45,251.96 | 121.45,251.96 121.96,251.45 A12.K2 | v70.14,178.8 70.65,179.31 76.74,179.31 v77.25,179.82 | v81.32,212.33 87.92,218.94 v102.14,218.94
D01RETURN
  Top 0.254: A15.E1 87.92,263.13 91.98,263.13 91.98,237.22 90.46,235.7 A14.R2
  Bottom 0.254: A14.R2 90.97,235.19 91.98,236.21 99.6,236.21 100.62,235.19 102.65,235.19 A13.R2 103.67,235.19 104.68,236.21 119.92,236.21 | 119.92,236.21 119.42,235.7 A12.R2 | 119.92,236.21 130.08,236.21 | 130.08,236.21 131.1,235.19 A11.R2 | 142.78,236.21 143.8,235.19 A10.R2 | 130.08,236.21 142.78,236.21 | 155.48,236.21 156.5,235.19 A09.R2 | 142.78,236.21 155.48,236.21 | 172.25,236.21 172.76,235.7 A08.R2 | 155.48,236.21 172.25,236.21 | 184.95,236.21 185.46,235.7 A07.R2 | 172.25,236.21 184.95,236.21 | 197.65,236.21 198.16,235.7 A06.R2 | 184.95,236.21 197.65,236.21 | 210.35,236.21 210.86,235.7 A05.R2 | 197.65,236.21 210.35,236.21 | 225.59,236.21 226.6,235.19 A04.R2 | 210.35,236.21 225.59,236.21 | 238.29,236.21 239.3,235.19 A03.R2 | 225.59,236.21 238.29,236.21 | 250.99,236.21 252,235.19 A02.R2 | 238.29,236.21 250.99,236.21 | 250.99,236.21 263.69,236.21 264.7,235.19 A01.R2
D01SELECTH  (via drill 0.61)
  Top 0.254: v63.03,59.42 63.03,72.12 64.04,73.14 64.04,77.71 63.54,78.22 63.54,90.41 67.09,93.97 67.09,115.81 68.11,116.83 C16.K2
  Bottom 0.254: v63.03,59.42 59.98,59.42 59.47,59.93 D17.E1
D01SELECTL  (via drill 0.61)
  Top 0.254: v37.12,59.42 34.58,61.96 v34.58,65.52 | v5.12,68.06 4.61,68.57 4.61,87.87 4.1,88.38 4.1,135.62 5.62,137.15 5.62,145.28 5.12,145.78 5.12,147.82 6.13,148.83 v6.13,156.45
  Bottom 0.254: v37.12,59.42 38.14,58.41 53.88,58.41 54.9,57.39 D17.F1 | v34.58,65.52 34.58,68.06 v5.12,68.06 | v6.13,156.45 9.69,160.01 34.58,160.01 35.6,158.99 B18.T2
D01SELH  (via drill 0.61)
  Top 0.254: v57.95,30.47 60.49,33.01 60.49,54.34 61,54.85 61,64 58.96,66.03 D17.C1
  Bottom 0.254: v57.95,30.47 48.3,30.47 46.77,28.94 D18.S1
D01SELL  (via drill 0.61)
  Top 0.254: v8.16,41.14 7.15,42.15 7.15,62.47 6.64,62.98 6.64,69.08 5.62,70.09 5.62,88.89 5.12,89.4 5.12,134.61 6.64,136.13 v6.64,146.8 | v45.76,148.32 48.3,148.32 48.3,151.88 B17.V2
  Bottom 0.254: v8.16,41.14 10.2,41.14 17.82,33.52 40.68,33.52 42.2,31.99 D18.R1 | v6.64,146.8 8.67,148.83 45.25,148.83 v45.76,148.32
D01SOURCE
  Bottom 0.254: A15.L1 84.87,247.38 89.95,247.38 A14.L2 90.97,247.89 93,247.89 94.02,248.91 101.64,248.91 | 101.64,248.91 102.65,247.89 A13.L2 | 117.38,248.91 118.4,247.89 A12.L2 | 117.38,248.91 101.64,248.91 | 130.08,248.91 131.1,247.89 A11.L2 | 130.08,248.91 117.38,248.91 | 142.78,248.91 143.8,247.89 A10.L2 | 142.78,248.91 130.08,248.91 | 155.48,248.91 156.5,247.89 A09.L2 | 155.48,248.91 142.78,248.91 | 172.25,248.91 172.76,248.4 A08.L2 | 172.25,248.91 155.48,248.91 | 184.95,248.91 185.46,248.4 A07.L2 | 184.95,248.91 172.25,248.91 | 197.65,248.91 198.16,248.4 A06.L2 | 197.65,248.91 184.95,248.91 | 210.35,248.91 210.86,248.4 A05.L2 | 210.35,248.91 197.65,248.91 | 225.59,248.91 226.6,247.89 A04.L2 | 225.59,248.91 210.35,248.91 | 238.29,248.91 239.3,247.89 A03.L2 | 238.29,248.91 225.59,248.91 | 250.99,248.91 252,247.89 A02.L2 | 250.99,248.91 238.29,248.91 | 250.99,248.91 263.69,248.91 264.7,247.89 A01.L2
D01STROBE
  Bottom 0.254: A15.P2 81.32,238.75 82.33,239.76 85.89,239.76 90.46,244.34 93,244.34 A14.M2 94.02,244.84 95.03,245.86 104.68,245.86 105.7,244.84 A13.M2 106.72,244.84 107.73,245.86 117.89,245.86 119.42,244.34 121.96,244.34 A12.M2 122.97,244.34 124.5,242.81 133.64,242.81 | 133.64,242.81 134.66,243.83 A11.M2 | 146.34,242.81 147.36,243.83 A10.M2 | 146.34,242.81 133.64,242.81 | 159.04,242.81 160.06,243.83 A09.M2 | 159.04,242.81 146.34,242.81 | 159.04,242.81 174.79,242.81 175.8,243.83 A08.M2 176.82,244.84 177.84,245.86 187.49,245.86 | 187.49,245.86 188.5,244.84 A07.M2 | 200.19,245.86 201.2,244.84 A06.M2 | 200.19,245.86 187.49,245.86 | 212.89,245.86 213.9,244.84 A05.M2 | 212.89,245.86 200.19,245.86 | 228.64,245.86 229.65,244.84 A04.M2 | 228.64,245.86 212.89,245.86 | 241.34,245.86 242.35,244.84 A03.M2 | 241.34,245.86 228.64,245.86 | 254.04,245.86 255.05,244.84 A02.M2 | 254.04,245.86 241.34,245.86 | 254.04,245.86 266.74,245.86 267.75,244.84 A01.M2
D01STROBEL  (via drill 0.61)
  Top 0.254: v66.58,244.34 66.58,240.27 68.11,238.75 A16.P2 | v41.69,255.51 38.14,251.96 v38.14,244.84 | v22.9,242.81 22.39,242.3 22.39,212.84 24.93,210.3 24.93,192.52 v29.5,187.95 | v31.02,186.42 31.53,185.92 31.53,179.31 34.58,176.26 34.58,164.58 35.6,163.56 v35.6,161.53 | v38.64,158.48 38.64,155.94 B18.U2
  Bottom 0.254: B18.U2 40.17,155.94 41.18,156.96 52.87,156.96 53.38,156.45 57.44,156.45 57.95,155.94 B17.U1 | v66.58,244.34 66.58,252.46 59.47,252.46 56.42,255.51 v41.69,255.51 | v38.14,244.84 36.61,243.32 34.58,243.32 34.07,242.81 v22.9,242.81 | v29.5,187.95 v31.02,186.42 | v35.6,161.53 v38.64,158.48
D01WRITE  (via drill 0.61)
  Top 0.254: v79.28,233.67 79.28,252.46 78.27,253.48 A15.J2
  Bottom 0.254: 95.03,233.16 94.02,232.14 A14.S2 | 95.03,233.16 101.13,233.16 102.65,231.64 105.7,231.64 A13.S2 106.72,232.14 110.78,232.14 111.8,233.16 113.32,233.16 114.84,231.64 121.96,231.64 A12.S2 122.97,231.64 124.5,230.11 133.64,230.11 | v79.28,233.67 79.79,233.16 95.03,233.16 | 133.64,230.11 134.66,231.13 A11.S2 | 146.34,230.11 147.36,231.13 A10.S2 | 133.64,230.11 146.34,230.11 | 159.04,230.11 160.06,231.13 A09.S2 | 146.34,230.11 159.04,230.11 | 159.04,230.11 174.79,230.11 175.8,231.13 A08.S2 176.82,232.14 177.84,233.16 187.49,233.16 | 187.49,233.16 188.5,232.14 A07.S2 | 200.19,233.16 201.2,232.14 A06.S2 | 187.49,233.16 200.19,233.16 | 212.89,233.16 213.9,232.14 A05.S2 | 200.19,233.16 212.89,233.16 | 228.64,233.16 229.65,232.14 A04.S2 | 212.89,233.16 228.64,233.16 | 241.34,233.16 242.35,232.14 A03.S2 | 228.64,233.16 241.34,233.16 | 254.04,233.16 255.05,232.14 A02.S2 | 241.34,233.16 254.04,233.16 | 254.04,233.16 266.74,233.16 267.75,232.14 A01.S2
D01WRITEH  (via drill 0.61)
  Top 0.254: v61.5,101.59 62.01,102.1 62.01,128.51 63.54,130.04 | 63.54,130.04 65.06,131.56 65.06,132.58 C16.D2 | 63.54,130.04 63.54,172.2 64.55,173.22 64.55,177.28 B16.L2
  Bottom 0.254: B16.L2 65.57,178.3 67.6,180.33 68.11,180.33 B16.K2 | v61.5,101.59 58.96,99.05 C17.S1
D02MEM0  (via drill 0.61)
  Top 0.254: v9.69,198.11 8.67,199.12 v8.67,261.61
  Bottom 0.254: v9.69,198.11 16.29,198.11 16.8,197.6 B20.D1 | v8.67,261.61 50.33,261.61 51.85,263.13 A17N.E2
D02MEM1  (via drill 0.61)
  Top 0.254: v20.86,209.79 18.83,207.76 18.83,204.71 21.88,201.66 21.88,199.63 20.86,198.62 20.86,194.04 B20.E1 | v45.25,209.79 46.26,210.81 46.26,223.51 47.79,225.03 47.79,231.13 50.84,234.18 50.84,255 52.36,256.53 A17N.H2
  Bottom 0.254: v45.25,209.79 v20.86,209.79
D02MEM2  (via drill 0.61)
  Top 0.254: v6.13,182.36 6.64,182.87 6.64,199.63 7.15,200.14 7.15,231.64 6.13,232.65 v6.13,240.78
  Bottom 0.254: v6.13,182.36 18.83,182.36 19.85,181.34 B20.K1 | v6.13,240.78 11.72,246.37 45.76,246.37 49.82,250.43 51.85,250.43 A17N.K2
D02MEM3  (via drill 0.61)
  Top 0.254: v7.66,179.31 7.66,198.62 8.16,199.12 8.16,240.27 v7.66,240.78
  Bottom 0.254: v7.66,179.31 15.78,179.31 16.8,178.3 B20.L1 | v7.66,240.78 12.74,245.86 50.84,245.86 51.85,244.84 A17N.M2
D02MEM4  (via drill 0.61)
  Top 0.254: v5.12,166.61 5.12,182.87 6.13,183.88 6.13,219.44 6.64,219.95 6.64,230.62 v6.13,231.13
  Bottom 0.254: v5.12,166.61 11.21,166.61 12.23,165.6 16.8,165.6 B20.R1 | v6.13,231.13 6.13,235.7 9.69,235.7 10.2,236.21 34.58,236.21 35.09,236.72 50.84,236.72 51.85,237.73 A17N.P2
D02MEM5  (via drill 0.61)
  Top 0.254: v8.67,160.52 8.16,161.02 8.16,177.28 6.64,178.8 6.64,179.82 7.15,180.33 7.15,199.12 7.66,199.63 7.66,232.65 v7.15,233.16
  Bottom 0.254: v8.67,160.52 18.83,160.52 19.85,161.53 B20.S1 | v7.15,233.16 50.84,233.16 51.85,232.14 A17N.S2
D02MEM6  (via drill 0.61)
  Top 0.254: v18.32,208.78 15.28,205.73 15.28,188.96 14.26,187.95 B20.H2 | v46.26,208.78 46.77,209.28 46.77,223 48.8,225.03 48.8,228.08 A17N.T2
  Bottom 0.254: v46.26,208.78 v18.32,208.78
D02MEM7  (via drill 0.61)
  Top 0.254: v45.25,197.09 47.28,199.12 47.28,219.44 49.31,221.48 A17N.V2
  Bottom 0.254: v45.25,197.09 33.56,185.41 16.29,185.41 15.78,184.9 11.21,184.9 B20.J2
D02MEM8  (via drill 0.61)
  Top 0.254: v8.67,196.58 8.67,174.23 10.7,172.2 B20.N2 | v3.59,198.11 3.59,257.04 v3.08,257.54
  Bottom 0.254: v8.67,196.58 7.15,198.11 v3.59,198.11 | v3.08,257.54 8.16,262.62 13.24,262.62 13.75,262.12 48.8,262.12 51.85,265.16 63.54,265.16 64.55,266.18 A16.D2
D02MEM9  (via drill 0.61)
  Top 0.254: v9.69,174.74 12.23,172.2 12.23,169.66 13.24,168.64 B20.P2 | v30.52,195.06 31.53,196.08 31.53,206.74 30.01,208.27 30.01,219.95 28.99,220.97 v28.99,225.03 | v28.99,227.06 25.44,230.62 v25.44,251.45
  Bottom 0.254: v9.69,174.74 5.62,174.74 4.61,175.76 4.61,183.88 6.13,183.88 12.74,190.49 12.74,195.06 v30.52,195.06 | v28.99,227.06 v28.99,225.03 | v25.44,251.45 32.55,258.56 43.22,258.56 43.72,259.07 61.5,259.07 65.57,263.13 67.6,263.13 A16.E2
D02MEM10  (via drill 0.61)
  Top 0.254: v14.26,147.31 14.26,154.93 B20.U2 | v218.98,147.82 222.03,150.86 222.03,270.75 v208.82,283.96 | v79.79,283.96 69.63,273.8 69.63,258.56 68.62,257.54 A16.H2
  Bottom 0.254: v14.26,147.31 15.28,146.29 35.6,146.29 36.1,145.78 65.57,145.78 68.62,148.83 88.43,148.83 89.44,147.82 105.19,147.82 105.7,148.32 110.27,148.32 111.8,146.8 135.16,146.8 136.18,147.82 v218.98,147.82 | v208.82,283.96 v79.79,283.96
D02MEM11  (via drill 0.61)
  Top 0.254: v9.18,170.68 9.18,164.58 9.69,164.07 9.69,160.01 9.18,159.5 9.18,153.91 10.2,152.9 B20.V2 | v20.86,171.69 21.37,172.2 21.37,173.72 24.93,177.28 24.93,185.92 v22.9,187.95 | v17.82,192.52 18.32,193.03 18.32,195.57 18.83,196.08 v18.83,201.16 | v61.5,201.66 61,202.17 61,219.95 62.01,220.97 62.01,231.13 64.55,233.67 69.63,233.67 69.63,249.42 68.62,250.43 A16.K2
  Bottom 0.254: v9.18,170.68 9.69,170.17 19.34,170.17 v20.86,171.69 | v22.9,187.95 18.32,192.52 v17.82,192.52 | v18.83,201.16 19.34,201.66 31.02,201.66 35.6,206.24 37.12,206.24 38.64,204.71 50.84,204.71 53.88,201.66 v61.5,201.66
D03BEMA0L  (via drill 0.61)
  Top 0.254: v64.04,9.13 59.98,13.2 59.98,21.32 59.47,21.83 D17.U1 | v213.4,9.13 275.88,71.62 275.88,258.56 268.26,266.18 265.72,266.18 A01.D2
  Bottom 0.254: A14.D2 90.97,267.2 91.48,267.7 95.54,267.7 96.05,268.21 98.08,268.21 99.1,267.2 102.65,267.2 A13.D2 103.67,267.2 104.18,267.7 108.24,267.7 108.75,268.21 110.78,268.21 112.3,266.69 A12.D2 119.42,267.2 120.43,268.21 129.58,268.21 | 129.58,268.21 131.1,266.69 A11.D2 | 142.28,268.21 143.8,266.69 A10.D2 | 142.28,268.21 129.58,268.21 | 154.98,268.21 156.5,266.69 A09.D2 | 154.98,268.21 142.28,268.21 | 171.74,268.21 172.76,267.2 A08.D2 | 171.74,268.21 154.98,268.21 | 184.44,268.21 185.46,267.2 A07.D2 | 184.44,268.21 171.74,268.21 | 197.14,268.21 198.16,267.2 A06.D2 | 197.14,268.21 184.44,268.21 | 209.84,268.21 210.86,267.2 A05.D2 | 209.84,268.21 197.14,268.21 | 225.59,268.21 226.6,267.2 A04.D2 | 225.59,268.21 209.84,268.21 | 238.29,268.21 239.3,267.2 A03.D2 | 238.29,268.21 225.59,268.21 | 238.29,268.21 250.99,268.21 252,267.2 A02.D2 253.02,267.2 254.04,268.21 263.69,268.21 264.7,267.2 A01.D2 | v213.4,9.13 v64.04,9.13
D03BEMA1L  (via drill 0.61)
  Top 0.254: v155.48,207.25 155.48,112.26 168.18,99.56 168.18,45.71 152.44,29.96 152.44,5.58 62.01,5.58 50.84,16.75 50.84,25.9 50.33,26.4 50.33,29.96 49.31,30.98 D17.R2 | v155.48,209.28 155.99,209.79 155.99,256.53 157.01,257.54 | 157.01,257.54 160.06,260.59 160.06,263.13 A09.E2 | 157.01,257.54 152.44,262.12 152.44,263.13 148.37,263.13 A10.E2
  Bottom 0.254: A01.E2 267.75,263.64 265.21,263.64 263.69,265.16 257.08,265.16 256.07,264.15 A02.E2 255.05,263.64 252.51,263.64 250.99,265.16 244.38,265.16 243.37,264.15 A03.E2 242.35,263.64 239.81,263.64 238.29,265.16 231.68,265.16 230.67,264.15 A04.E2 229.65,263.64 226.6,263.64 225.08,265.16 216.44,265.16 214.92,263.64 A05.E2 213.9,264.15 210.35,264.15 209.33,265.16 203.74,265.16 202.22,263.64 A06.E2 201.2,264.15 197.65,264.15 196.63,265.16 191.04,265.16 189.52,263.64 A07.E2 188.5,264.15 184.95,264.15 183.93,265.16 178.34,265.16 176.82,263.64 A08.E2 175.8,264.15 175.3,264.66 167.68,264.66 167.17,265.16 162.6,265.16 161.07,263.64 A09.E2 | A14.E2 94.02,264.15 95.03,265.16 101.64,265.16 103.16,263.64 105.7,263.64 A13.E2 106.72,264.15 107.22,264.66 111.8,264.66 112.3,265.16 117.38,265.16 118.4,264.15 121.96,264.15 A12.E2 122.97,263.64 124.5,265.16 130.08,265.16 131.1,264.15 134.66,264.15 A11.E2 135.67,263.64 137.2,265.16 142.78,265.16 143.8,264.15 147.36,264.15 A10.E2 | v155.48,209.28 v155.48,207.25
D03BEMA2L  (via drill 0.61)
  Top 0.254: v155.99,75.68 155.99,46.22 130.59,20.82 130.59,9.13 65.57,9.13 60.49,14.21 60.49,23.86 57.95,23.86 57.44,23.36 57.44,21.32 55.92,19.8 D17.V1
  Bottom 0.254: 104.68,258.56 95.03,258.56 94.02,257.54 A14.H2 | 104.68,258.56 105.7,257.54 A13.H2 | 104.68,258.56 120.94,258.56 121.96,257.54 A12.H2 122.97,257.04 124.5,255.51 129.07,255.51 129.58,256.02 134.15,256.02 134.66,256.53 A11.H2 135.67,257.04 137.2,255.51 141.77,255.51 142.78,256.53 147.36,256.53 A10.H2 148.37,257.04 149.9,255.51 154.47,255.51 154.98,256.02 159.55,256.02 160.06,256.53 A09.H2 161.07,257.04 162.09,256.02 166.15,256.02 166.66,255.51 174.28,255.51 175.3,256.53 175.8,256.53 A08.H2 176.82,257.54 177.84,258.56 187.49,258.56 | 187.49,258.56 188.5,257.54 A07.H2 | 200.19,258.56 201.2,257.54 A06.H2 | 200.19,258.56 187.49,258.56 | 212.89,258.56 213.9,257.54 A05.H2 | 212.89,258.56 200.19,258.56 | 228.64,258.56 229.65,257.54 A04.H2 | 228.64,258.56 212.89,258.56 | 241.34,258.56 242.35,257.54 A03.H2 | 241.34,258.56 228.64,258.56 | 241.34,258.56 254.04,258.56 255.05,257.54 A02.H2 256.07,257.54 257.08,258.56 266.74,258.56 267.75,257.54 A01.H2 268.77,256.53 269.78,255.51 276.39,255.51 276.39,91.43 271.82,86.86 267.75,86.86 256.07,75.17 156.5,75.17 v155.99,75.68
D03BMA0  (via drill 0.61)
  Top 0.254: v76.24,238.75 76.24,199.12 77.76,197.6 B15.D2
  Bottom 0.254: v76.24,238.75 75.22,239.76 5.62,239.76 5.12,240.27 5.12,247.89 9.18,247.89 11.72,250.43 13.75,250.43 A20N.K2
D03BMA1  (via drill 0.61)
  Top 0.254: v20.36,221.48 18.83,223 18.83,236.21 16.29,238.75 16.29,242.3 14.77,243.83 A20N.M2 | v61,221.48 60.49,220.97 60.49,196.08 61,195.57 61,191.5 v60.49,191 | v81.82,188.96 82.33,188.46 82.33,182.36 81.32,181.34 B15.K2
  Bottom 0.254: v20.36,221.48 20.86,220.97 60.49,220.97 v61,221.48 | v60.49,191 62.52,188.96 v81.82,188.96
D03BMA2  (via drill 0.61)
  Top 0.254: v83.35,163.56 82.84,164.07 82.84,185.41 v84.36,186.93 | v93,188.96 92.49,189.47 v92.49,201.16 | v86.9,204.71 85.89,205.73 85.89,229.1 v86.4,229.6 | v16.29,227.06 15.78,227.57 15.78,236.72 14.77,237.73 A20N.P2
  Bottom 0.254: v83.35,163.56 79.28,163.56 78.27,164.58 B15.R2 | v84.36,186.93 86.4,188.96 v93,188.96 | v92.49,201.16 90.46,201.16 v86.9,204.71 | v86.4,229.6 85.89,230.11 64.04,230.11 63.54,229.6 58.96,229.6 56.42,227.06 47.79,227.06 46.77,228.08 45.25,228.08 41.18,224.02 24.42,224.02 21.37,227.06 v16.29,227.06
D03BMA3  (via drill 0.61)
  Top 0.254: v52.87,208.78 53.38,208.27 55.41,208.27 v55.41,208.78 | v68.62,208.78 69.63,207.76 72.68,207.76 v72.68,208.78 | v102.65,209.28 105.19,206.74 105.19,191 111.29,184.9 111.29,178.3 114.34,175.25 114.34,174.23 112.81,172.71 104.68,172.71 104.68,150.36 104.18,149.85 104.18,147.82 105.7,146.29 107.22,146.29 107.22,144.26 107.73,143.75 107.73,141.72 v107.22,141.21
  Bottom 0.254: v52.87,208.78 51.34,208.78 40.17,219.95 14.26,219.95 13.75,219.44 4.61,219.44 4.61,225.54 11.21,232.14 13.75,232.14 A20N.S2 | v68.62,208.78 v55.41,208.78 | v72.68,208.78 97.57,208.78 98.08,209.28 v102.65,209.28 | v107.22,141.21 104.68,141.21 104.18,141.72 100.62,141.72 100.11,141.21 89.44,141.21 87.92,142.74 C15.A1
D03BMA4  (via drill 0.61)
  Top 0.254: v19.85,223.51 19.34,224.02 19.34,232.65 v20.86,234.18 | v101.13,236.21 101.64,235.7 101.64,234.18 v103.16,232.65 | v107.73,233.16 116.88,224.02 116.88,169.15 v117.38,168.64 | v110.78,166.61 110.78,162.55 108.24,160.01 108.24,157.47 v108.75,156.96 | v87.41,151.37 85.89,149.85 85.89,129.53 v86.9,128.51
  Bottom 0.254: v19.85,223.51 11.72,223.51 11.72,228.08 A20N.T2 | v20.86,234.18 21.37,233.67 33.06,233.67 35.6,236.21 90.97,236.21 91.48,236.72 100.62,236.72 v101.13,236.21 | v103.16,232.65 103.67,233.16 v107.73,233.16 | v117.38,168.64 115.35,166.61 v110.78,166.61 | v108.75,156.96 108.24,157.47 93.51,157.47 v87.41,151.37 | v86.9,128.51 85.38,126.99 C15.F1
D03BMA5  (via drill 0.61)
  Top 0.254: v15.78,221.48 17.31,219.95 20.86,219.95 v20.86,218.94 | v35.6,212.33 36.61,211.32 v36.61,205.22 | v42.2,201.16 43.22,200.14 v43.22,199.12 | v101.13,198.62 101.64,198.11 101.64,191 98.59,187.95 98.59,147.31 99.1,146.8 99.1,144.26 98.08,143.24 98.08,130.54 v93.51,125.97 | v90.97,123.43 88.94,121.4 88.94,113.27 87.41,111.75 C15.M1
  Bottom 0.254: v15.78,221.48 12.23,221.48 11.72,221.98 A20N.V2 | v20.86,218.94 27.47,212.33 v35.6,212.33 | v36.61,205.22 40.68,201.16 v42.2,201.16 | v43.22,199.12 44.23,198.11 56.93,198.11 57.44,197.6 63.54,197.6 64.04,198.11 73.19,198.11 73.7,197.6 76.24,197.6 76.74,198.11 85.89,198.11 86.4,197.6 88.94,197.6 89.95,198.62 v101.13,198.62 | v93.51,125.97 v90.97,123.43
D03BMA6  (via drill 0.61)
  Top 0.254: v81.32,75.68 81.32,87.36 76.24,92.44 76.24,114.8 78.27,116.83 78.27,117.84 79.79,119.37 79.79,130.54 77.76,132.58 C15.D2 | v93.51,75.68 95.03,74.16 95.03,16.75 v98.08,13.7 | v270.29,270.24 245.4,295.14 41.18,295.14 41.18,286.5 38.64,283.96 25.44,283.96 25.44,271.77 24.42,270.75 24.42,267.2 A19N.D2
  Bottom 0.254: v93.51,75.68 v81.32,75.68 | v98.08,13.7 98.59,14.21 270.29,14.21 278.93,22.85 278.93,268.21 272.32,268.21 v270.29,270.24
D03BMA7  (via drill 0.61)
  Top 0.254: v109.76,281.93 117.89,273.8 117.89,258.56 133.64,242.81 133.64,224.02 135.16,222.49 v135.16,216.4 | v135.67,208.78 136.18,208.27 136.18,148.32 133.64,145.78 133.64,143.75 120.43,130.54 120.43,124.96 118.91,123.43 v118.91,122.42 | v81.32,120.38 81.32,117.84 C15.K2
  Bottom 0.254: v109.76,281.93 36.61,281.93 26.45,271.77 12.74,271.77 12.74,269.23 13.75,268.21 26.96,268.21 26.96,264.15 A19N.E2 | v135.16,216.4 135.16,208.78 v135.67,208.78 | v118.91,122.42 84.87,122.42 84.36,121.91 82.84,121.91 v81.32,120.38
D03BMA8  (via drill 0.61)
  Top 0.254: v95.54,86.35 v95.54,97.52 | v103.16,85.33 111.29,93.46 111.29,140.2 111.8,140.7 111.8,141.72 111.29,142.23 111.29,146.29 v113.32,148.32 | v179.87,150.36 193.58,164.07 193.58,252.97 199.68,259.07 199.68,261.61 193.08,268.21 174.79,268.21 174.79,277.86 175.3,278.37 v175.3,279.9 | v37.63,282.94 25.44,270.75 25.44,258.56 26.45,257.54 A19N.H2
  Bottom 0.254: v95.54,97.52 95.03,97.02 86.4,97.02 83.35,100.06 79.28,100.06 78.27,101.08 C15.R2 | v95.54,86.35 96.56,85.33 v103.16,85.33 | v113.32,148.32 114.34,149.34 178.85,149.34 v179.87,150.36 | v175.3,279.9 173.26,281.93 111.29,281.93 110.27,282.94 v37.63,282.94
D03BMA9  (via drill 0.61)
  Top 0.254: v28.99,270.24 28.99,252.97 27.47,251.45 A19N.K2 | v98.08,274.31 101.64,270.75 101.64,253.48 102.65,252.46 107.73,252.46 107.73,245.35 117.38,235.7 117.38,202.68 123.99,196.08 123.99,187.95 133.13,178.8 133.13,144.77 v123.99,135.62 | v74.71,132.07 73.19,133.59 73.19,139.18 74.71,140.7 74.71,142.23 C16.A1
  Bottom 0.254: v28.99,270.24 30.52,271.77 86.9,271.77 89.44,274.31 v98.08,274.31 | v123.99,135.62 123.48,135.12 89.44,135.12 86.4,132.07 v74.71,132.07
D03BMA10  (via drill 0.61)
  Top 0.254: v28.99,250.43 28.99,246.37 27.47,244.84 A19N.M2 | v57.95,252.46 57.44,251.96 57.44,220.46 v58.96,218.94 | v62.01,217.92 61.5,217.41 61.5,203.19 62.52,202.17 62.52,198.62 61.5,197.6 61.5,148.83 57.44,144.77 v57.44,129.02
  Bottom 0.254: v28.99,250.43 31.02,252.46 v57.95,252.46 | v58.96,218.94 59.98,217.92 v62.01,217.92 | v57.44,129.02 57.95,128.51 65.57,128.51 66.58,127.5 71.16,127.5 C16.F1
D03BMA11  (via drill 0.61)
  Top 0.254: v258.61,10.15 276.9,28.44 276.9,268.21 229.65,268.21 228.64,269.23 228.64,294.63 61,294.63 32.04,265.67 32.04,238.75 27.47,238.75 A19N.P2 | v66.08,10.15 61,15.23 61,53.84 61.5,54.34 v61.5,94.98
  Bottom 0.254: v258.61,10.15 v66.08,10.15 | v61.5,94.98 63.54,97.02 69.12,97.02 76.24,104.13 76.24,110.73 75.22,110.73 C16.M1
D03BTP2  (via drill 0.61)
  Top 0.254: v40.68,65.01 41.18,65.52 41.18,71.11 42.2,72.12 42.2,87.36 41.18,88.38 v41.18,88.89 | v41.69,92.44 41.69,97.02 43.22,98.54 43.22,99.56 42.71,100.06 42.2,100.06 41.69,100.57 41.69,134.1 41.18,134.61 v41.18,137.66 | v5.62,220.46 5.62,184.39 4.61,183.38 4.61,167.63 4.1,167.12 v4.1,144.26
  Bottom 0.254: v40.68,65.01 42.2,63.49 D18.D1 | v41.18,88.89 41.18,92.44 v41.69,92.44 | 41.69,138.16 v41.18,137.66 | 41.69,138.16 50.33,138.16 51.85,139.69 C17.B1 | v5.62,220.46 63.03,220.46 64.55,221.98 A16.V2 | v4.1,144.26 10.2,138.16 41.69,138.16
D03EA0  (via drill 0.61)
  Top 0.254: v84.36,249.92 88.94,245.35 v88.94,240.27 | v96.05,239.76 95.54,239.26 95.54,219.44 87.92,211.82 87.92,206.74 B15.A1
  Bottom 0.254: v84.36,249.92 83.86,249.42 69.63,249.42 69.63,255.51 72.68,258.56 72.68,261.61 66.08,268.21 38.14,268.21 37.12,267.2 A18N.D2 | v88.94,240.27 89.44,239.76 v96.05,239.76
D03EA1  (via drill 0.61)
  Top 0.254: v83.35,224.52 82.33,223.51 82.33,192.52 83.86,191 B15.F1 | v46.26,227.06 44.74,228.59 44.74,256.02 40.17,260.59 40.17,263.13 A18N.E2
  Bottom 0.254: v83.35,224.52 82.84,224.02 49.82,224.02 46.77,227.06 v46.26,227.06
D03EA2  (via drill 0.61)
  Top 0.254: v83.35,215.89 85.38,213.86 85.38,194.55 85.89,194.04 85.89,176.26 86.9,175.25 B15.M1 | v74.71,218.94 72.68,220.97 72.68,248.91 v67.6,253.99
  Bottom 0.254: v83.35,215.89 80.3,218.94 v74.71,218.94 | v67.6,253.99 63.03,258.56 44.23,258.56 43.22,257.54 40.17,257.54 A18N.H2
D03EMA0H  (via drill 0.61)
  Top 0.254: D19.H1 34.07,54.34 36.1,56.38 36.1,56.88 D18.F2 | D17.P1 58.96,35.55 59.98,36.56 v59.98,55.36 59.98,56.88 57.44,59.42 57.44,71.11 v53.38,75.17 | v56.93,184.39 56.93,191 56.42,191.5 56.42,195.06 55.41,196.08 B17.D1 | v60.49,183.38 61,182.87 61,152.9 v55.41,147.31 | v36.61,146.8 35.09,145.28 35.09,129.02 v35.6,128.51 | v29.5,122.42 28.48,121.4 28.48,114.8 25.44,111.75 25.44,108.7 32.04,102.1 32.04,87.87 v34.07,85.84
  Bottom 0.254: v59.98,55.36 59.47,55.87 38.14,55.87 37.12,56.88 D18.F2 | v56.93,184.39 57.95,183.38 v60.49,183.38 | v55.41,147.31 54.9,146.8 v36.61,146.8 | v29.5,122.42 v35.6,128.51 | v34.07,85.84 44.23,75.68 51.85,75.68 52.36,75.17 v53.38,75.17
D03EMA0L  (via drill 0.61)
  Top 0.254: D18.C1 45.76,66.03 41.69,66.03 41.69,64.5 39.66,62.47 39.66,60.95 D18.E2 | v59.98,195.06 59.98,204.71 58.96,205.73 B17.A1 | v44.23,15.23 31.53,27.93 31.53,49.26 30.52,50.28 D19.J1 | v171.23,198.62 v171.23,16.75 | v115.86,198.62 114.34,200.14 v114.34,215.89 | v97.06,219.95 88.94,211.82 88.94,203.7 85.89,200.65 85.89,195.06 86.9,194.04 B15.E1
  Bottom 0.254: D19.J1 30.52,51.3 30.52,55.87 32.04,55.87 36.61,60.44 39.15,60.44 D18.E2 | v59.98,195.06 85.89,195.06 86.9,194.04 B15.E1 | v44.23,15.23 169.71,15.23 v171.23,16.75 | v115.86,198.62 v171.23,198.62 | v114.34,215.89 110.27,219.95 v97.06,219.95
D03EMA1H  (via drill 0.61)
  Top 0.254: D17.M2 51.85,41.64 50.84,42.66 50.84,47.23 46.77,47.23 D18.K1 45.76,48.25 44.74,49.26 44.74,57.9 v40.68,61.96 | v52.87,192.01 53.38,191.5 53.38,167.12 52.87,167.12 52.87,165.09 v50.33,162.55 | v45.25,163.56 44.23,162.55 44.23,156.45 v43.72,155.94 | v43.72,153.91 44.23,153.4 44.23,151.88 43.22,150.86 v43.22,147.82 | v20.86,147.31 19.34,145.78 19.34,134.61 v19.85,134.1 | v23.4,106.16 31.53,98.03 31.53,68.06 v30.52,67.04 | v33.06,64.5 33.06,60.95 D19.E1
  Bottom 0.254: v40.68,61.96 35.6,61.96 34.07,60.44 D19.E1 | v52.87,192.01 56.93,192.01 57.95,193.03 B17.E1 | v50.33,162.55 49.31,163.56 v45.25,163.56 | v43.72,153.91 v43.72,155.94 | v43.22,147.82 26.45,147.82 25.44,146.8 21.37,146.8 v20.86,147.31 | v19.85,134.1 19.34,134.1 18.83,134.61 10.2,134.61 7.66,132.07 7.66,106.16 v23.4,106.16 | v33.06,64.5 v30.52,67.04
D03EMA1L  (via drill 0.61)
  Top 0.254: B17.B1 55.92,202.68 56.93,201.66 56.93,192.01 59.98,188.96 59.98,184.39 59.47,183.88 59.47,181.85 59.98,181.34 v59.98,179.82 60.49,179.31 60.49,153.91 v55.41,148.83 | v6.13,61.96 6.13,68.57 5.12,69.58 5.12,88.38 4.61,88.89 4.61,135.12 6.13,136.64 6.13,145.78 5.62,146.29 5.62,147.31 v7.15,148.83
  Bottom 0.254: 28.99,61.96 30.01,62.98 D19.D1 | 28.99,61.96 28.99,49.77 29.5,49.26 38.14,49.26 39.66,50.79 D18.J1 | v59.98,179.82 63.54,176.26 82.84,176.26 83.86,177.28 B15.L1 | v6.13,61.96 28.99,61.96 | v7.15,148.83 7.66,149.34 46.26,149.34 46.77,148.83 v55.41,148.83
D03EMA2H
  Top 0.254: D17.T2 48.8,25.9 47.28,27.42 47.28,29.96 36.61,40.63 36.61,43.68 D18.L2
  Bottom 0.254: D19.L1 30.52,44.18 36.1,44.18 D18.L2
D03EMA2L  (via drill 0.61)
  Top 0.254: v85.89,165.09 85.38,165.6 v85.38,167.63 | v7.15,169.66 7.66,169.15 7.66,149.85 8.16,149.34 8.16,146.8 7.15,145.78 7.15,134.61 6.13,133.59 6.13,70.6 7.15,69.58 7.15,63.49 7.66,62.98 7.66,43.17 v8.16,42.66
  Bottom 0.254: D18.K2 39.15,47.23 39.15,44.69 37.63,43.17 35.6,43.17 34.07,41.64 D19.M1 33.06,41.64 32.04,42.66 v8.16,42.66 | v85.89,165.09 86.9,165.09 86.9,162.55 B15.S1 | v85.38,167.63 83.35,169.66 41.69,169.66 41.18,170.17 20.36,170.17 19.85,169.66 v7.15,169.66
D03MA0L  (via drill 0.61)
  Top 0.254: v86.9,265.16 85.89,264.15 85.89,253.48 82.84,250.43 82.84,235.7 82.33,235.19 82.33,224.52 79.28,221.48 79.28,189.98 78.78,189.47 78.78,185.92 77.76,184.9 B15.J2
